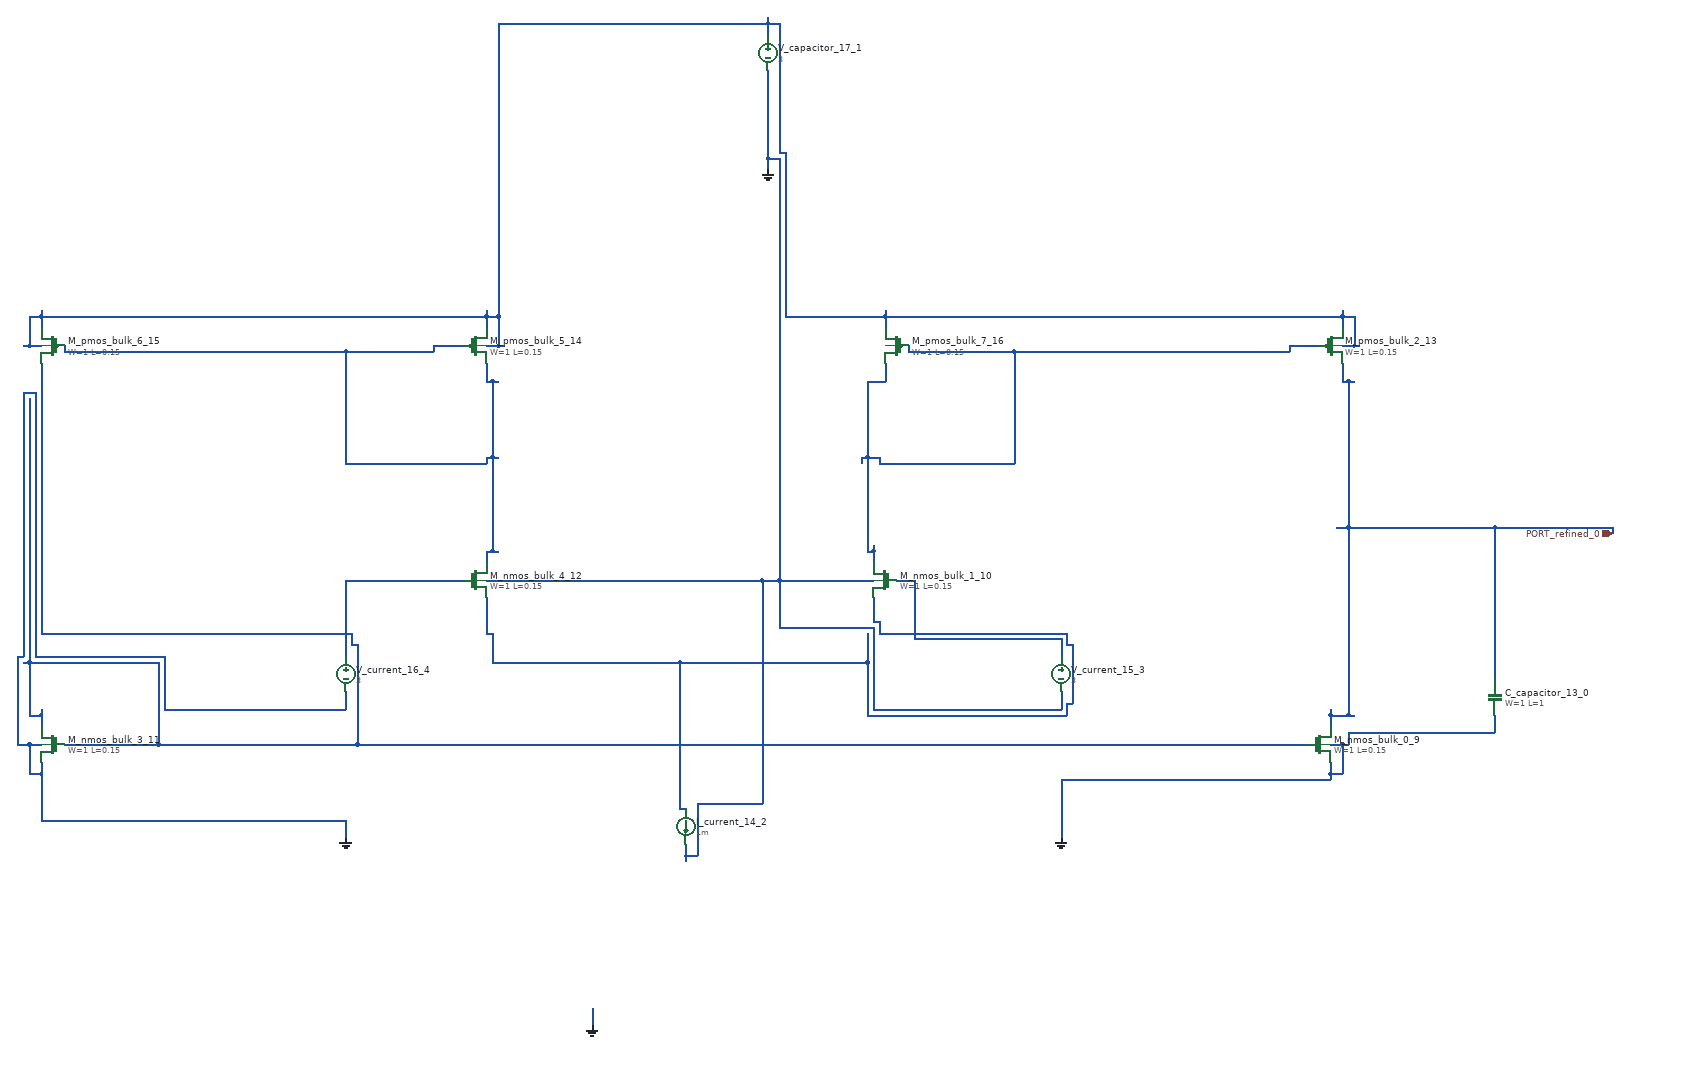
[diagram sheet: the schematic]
v {xschem version=3.4.8 file_version=1.2}
G {}
K {}
V {}
S {}
E {}
C {sky130_fd_pr/cap_mim_m3_1.sym} 3100 1320 2 0 {name="C_capacitor_13_0" model=cap_mim_m3_1 W=1 L=1 MF=1 spiceprefix=X}
C {devices/vsource.sym} 1860 220 0 0 {name="V_capacitor_17_1" value=3 savecurrent=false}
C {devices/isource.sym} 1720 1540 0 0 {name="I_current_14_2" value=1m}
C {devices/vsource.sym} 2360 1280 0 0 {name="V_current_15_3" value=3 savecurrent=false}
C {devices/vsource.sym} 1140 1280 0 0 {name="V_current_16_4" value=3 savecurrent=false}
C {devices/gnd.sym} 1140 1560 0 0 {name="l_gnd_10_5" lab="GND"}
C {devices/gnd.sym} 1560 1880 0 0 {name="l_gnd_11_6" lab="GND"}
C {devices/gnd.sym} 1860 420 0 0 {name="l_gnd_12_7" lab="GND"}
C {devices/gnd.sym} 2360 1560 0 0 {name="l_gnd_9_8" lab="GND"}
C {sky130_fd_pr/nfet_01v8.sym} 2800 1400 0 0 {name="M_nmos_bulk_0_9"
W=1
L=0.15
nf=1 
mult=1
ad="expr('int((@nf + 1)/2) * @W / @nf * 0.29')"
pd="expr('2*int((@nf + 1)/2) * (@W / @nf + 0.29)')"
as="expr('int((@nf + 2)/2) * @W / @nf * 0.29')"
ps="expr('2*int((@nf + 2)/2) * (@W / @nf + 0.29)')"
nrd="expr('0.29 / @W ')" nrs="expr('0.29 / @W ')"
sa=0 sb=0 sd=0
model=nfet_01v8
spiceprefix=X
}
C {sky130_fd_pr/nfet_01v8.sym} 2060 1120 0 1 {name="M_nmos_bulk_1_10"
W=1
L=0.15
nf=1 
mult=1
ad="expr('int((@nf + 1)/2) * @W / @nf * 0.29')"
pd="expr('2*int((@nf + 1)/2) * (@W / @nf + 0.29)')"
as="expr('int((@nf + 2)/2) * @W / @nf * 0.29')"
ps="expr('2*int((@nf + 2)/2) * (@W / @nf + 0.29)')"
nrd="expr('0.29 / @W ')" nrs="expr('0.29 / @W ')"
sa=0 sb=0 sd=0
model=nfet_01v8
spiceprefix=X
}
C {sky130_fd_pr/nfet_01v8.sym} 640 1400 0 1 {name="M_nmos_bulk_3_11"
W=1
L=0.15
nf=1 
mult=1
ad="expr('int((@nf + 1)/2) * @W / @nf * 0.29')"
pd="expr('2*int((@nf + 1)/2) * (@W / @nf + 0.29)')"
as="expr('int((@nf + 2)/2) * @W / @nf * 0.29')"
ps="expr('2*int((@nf + 2)/2) * (@W / @nf + 0.29)')"
nrd="expr('0.29 / @W ')" nrs="expr('0.29 / @W ')"
sa=0 sb=0 sd=0
model=nfet_01v8
spiceprefix=X
}
C {sky130_fd_pr/nfet_01v8.sym} 1360 1120 0 0 {name="M_nmos_bulk_4_12"
W=1
L=0.15
nf=1 
mult=1
ad="expr('int((@nf + 1)/2) * @W / @nf * 0.29')"
pd="expr('2*int((@nf + 1)/2) * (@W / @nf + 0.29)')"
as="expr('int((@nf + 2)/2) * @W / @nf * 0.29')"
ps="expr('2*int((@nf + 2)/2) * (@W / @nf + 0.29)')"
nrd="expr('0.29 / @W ')" nrs="expr('0.29 / @W ')"
sa=0 sb=0 sd=0
model=nfet_01v8
spiceprefix=X
}
C {sky130_fd_pr/pfet_01v8.sym} 2820 720 0 0 {name="M_pmos_bulk_2_13"
W=1
L=0.15
nf=1
mult=1
ad="expr('int((@nf + 1)/2) * @W / @nf * 0.29')"
pd="expr('2*int((@nf + 1)/2) * (@W / @nf + 0.29)')"
as="expr('int((@nf + 2)/2) * @W / @nf * 0.29')"
ps="expr('2*int((@nf + 2)/2) * (@W / @nf + 0.29)')"
nrd="expr('0.29 / @W ')" nrs="expr('0.29 / @W ')"
sa=0 sb=0 sd=0
model=pfet_01v8
spiceprefix=X
}
C {sky130_fd_pr/pfet_01v8.sym} 1360 720 0 0 {name="M_pmos_bulk_5_14"
W=1
L=0.15
nf=1
mult=1
ad="expr('int((@nf + 1)/2) * @W / @nf * 0.29')"
pd="expr('2*int((@nf + 1)/2) * (@W / @nf + 0.29)')"
as="expr('int((@nf + 2)/2) * @W / @nf * 0.29')"
ps="expr('2*int((@nf + 2)/2) * (@W / @nf + 0.29)')"
nrd="expr('0.29 / @W ')" nrs="expr('0.29 / @W ')"
sa=0 sb=0 sd=0
model=pfet_01v8
spiceprefix=X
}
C {sky130_fd_pr/pfet_01v8.sym} 640 720 0 1 {name="M_pmos_bulk_6_15"
W=1
L=0.15
nf=1
mult=1
ad="expr('int((@nf + 1)/2) * @W / @nf * 0.29')"
pd="expr('2*int((@nf + 1)/2) * (@W / @nf + 0.29)')"
as="expr('int((@nf + 2)/2) * @W / @nf * 0.29')"
ps="expr('2*int((@nf + 2)/2) * (@W / @nf + 0.29)')"
nrd="expr('0.29 / @W ')" nrs="expr('0.29 / @W ')"
sa=0 sb=0 sd=0
model=pfet_01v8
spiceprefix=X
}
C {sky130_fd_pr/pfet3_01v8.sym} 2080 720 0 1 {name="M_pmos_bulk_7_16"
W=1
L=0.15
body=VDD
nf=1
mult=1
ad="expr('int((@nf + 1)/2) * @W / @nf * 0.29')"
pd="expr('2*int((@nf + 1)/2) * (@W / @nf + 0.29)')"
as="expr('int((@nf + 2)/2) * @W / @nf * 0.29')"
ps="expr('2*int((@nf + 2)/2) * (@W / @nf + 0.29)')"
nrd="expr('0.29 / @W ')" nrs="expr('0.29 / @W ')"
sa=0 sb=0 sd=0
model=pfet_01v8
spiceprefix=X
}
C {devices/ipin.sym} 3300 1040 0 0 {name="p_port_8_17" lab="PORT_refined_0"}
N 2820 1350 2850 1350 {}
N 2850 1350 2860 1350 {}
N 2830 1030 2850 1030 {}
N 2850 1030 3100 1030 {}
N 3100 1030 3300 1030 {}
N 2840 780 2850 780 {}
N 2850 780 2860 780 {}
N 2820 1370 2820 1350 {}
N 2820 1350 2820 1340 {}
N 2840 780 2840 750 {}
N 2850 1350 2850 1030 {}
N 2850 1030 2850 780 {}
N 3100 1300 3100 1290 {}
N 3100 1290 3100 1030 {}
N 3300 1040 3300 1030 {}
N 1720 1590 1740 1590 {}
N 620 1530 1140 1530 {}
N 1740 1500 1850 1500 {}
N 2360 1460 2820 1460 {}
N 600 1450 620 1450 {}
N 2820 1450 2840 1450 {}
N 580 1400 600 1400 {}
N 600 1400 620 1400 {}
N 2820 1400 2840 1400 {}
N 2840 1400 2850 1400 {}
N 2850 1380 3100 1380 {}
N 830 1340 1140 1340 {}
N 2040 1340 2360 1340 {}
N 580 1250 590 1250 {}
N 610 1250 830 1250 {}
N 1880 1200 2040 1200 {}
N 1380 1120 1850 1120 {}
N 1850 1120 1880 1120 {}
N 1880 1120 2040 1120 {}
N 590 800 610 800 {}
N 1860 400 1880 400 {}
N 580 1400 580 1250 {}
N 590 1250 590 800 {}
N 600 1450 600 1400 {}
N 610 1250 610 800 {}
N 620 1530 620 1450 {}
N 620 1450 620 1430 {}
N 830 1340 830 1250 {}
N 1140 1560 1140 1530 {}
N 1140 1340 1140 1310 {}
N 1560 1880 1560 1850 {}
N 1720 1600 1720 1590 {}
N 1720 1590 1720 1570 {}
N 1740 1590 1740 1500 {}
N 1850 1500 1850 1120 {}
N 1860 420 1860 400 {}
N 1860 400 1860 250 {}
N 1880 1200 1880 1120 {}
N 1880 1120 1880 400 {}
N 2040 1340 2040 1200 {}
N 2360 1560 2360 1460 {}
N 2360 1340 2360 1310 {}
N 2820 1460 2820 1450 {}
N 2820 1450 2820 1430 {}
N 2840 1450 2840 1400 {}
N 2850 1400 2850 1380 {}
N 3100 1380 3100 1350 {}
N 660 1400 820 1400 {}
N 820 1400 1160 1400 {}
N 1160 1400 2780 1400 {}
N 600 1350 620 1350 {}
N 590 1260 600 1260 {}
N 600 1260 820 1260 {}
N 1150 1230 1160 1230 {}
N 620 1210 1150 1210 {}
N 600 1350 600 1260 {}
N 600 1260 600 810 {}
N 620 1370 620 1350 {}
N 620 1350 620 1340 {}
N 620 1210 620 750 {}
N 820 1400 820 1260 {}
N 1150 1230 1150 1210 {}
N 1160 1400 1160 1230 {}
N 1710 1510 1720 1510 {}
N 2030 1350 2370 1350 {}
N 2370 1330 2380 1330 {}
N 1390 1260 1710 1260 {}
N 1710 1260 2030 1260 {}
N 2370 1230 2380 1230 {}
N 1380 1210 1390 1210 {}
N 2050 1210 2370 1210 {}
N 2040 1190 2050 1190 {}
N 1380 1210 1380 1150 {}
N 1390 1260 1390 1210 {}
N 1710 1510 1710 1260 {}
N 2030 1350 2030 1260 {}
N 2030 1260 2030 1210 {}
N 2040 1190 2040 1150 {}
N 2050 1210 2050 1190 {}
N 2370 1350 2370 1330 {}
N 2370 1230 2370 1210 {}
N 2380 1330 2380 1230 {}
N 590 720 600 720 {}
N 600 720 620 720 {}
N 1380 720 1400 720 {}
N 1400 720 1410 720 {}
N 2840 720 2860 720 {}
N 2860 720 2870 720 {}
N 600 670 620 670 {}
N 620 670 1380 670 {}
N 1380 670 1400 670 {}
N 1890 670 2060 670 {}
N 2060 670 2840 670 {}
N 2840 670 2860 670 {}
N 1880 390 1890 390 {}
N 1400 170 1860 170 {}
N 1860 170 1880 170 {}
N 600 720 600 670 {}
N 620 690 620 670 {}
N 620 670 620 660 {}
N 1380 690 1380 670 {}
N 1380 670 1380 660 {}
N 1400 720 1400 670 {}
N 1400 670 1400 170 {}
N 1860 190 1860 170 {}
N 1860 170 1860 160 {}
N 1880 390 1880 170 {}
N 1890 670 1890 390 {}
N 2060 690 2060 670 {}
N 2060 670 2060 660 {}
N 2840 690 2840 670 {}
N 2840 670 2840 660 {}
N 2860 720 2860 670 {}
N 2030 1070 2040 1070 {}
N 2050 920 2280 920 {}
N 2020 910 2030 910 {}
N 2030 910 2050 910 {}
N 2030 780 2060 780 {}
N 2100 730 2280 730 {}
N 2280 730 2750 730 {}
N 2750 720 2800 720 {}
N 2020 920 2020 910 {}
N 2030 1070 2030 910 {}
N 2030 910 2030 780 {}
N 2040 1090 2040 1070 {}
N 2040 1070 2040 1060 {}
N 2050 920 2050 910 {}
N 2060 780 2060 750 {}
N 2100 730 2100 720 {}
N 2280 920 2280 730 {}
N 2750 730 2750 720 {}
N 2110 1220 2360 1220 {}
N 2080 1120 2110 1120 {}
N 2110 1220 2110 1120 {}
N 2360 1250 2360 1220 {}
N 1380 1070 1390 1070 {}
N 1390 1070 1400 1070 {}
N 1140 920 1380 920 {}
N 1380 910 1390 910 {}
N 1390 910 1400 910 {}
N 1380 780 1390 780 {}
N 1390 780 1400 780 {}
N 660 730 1140 730 {}
N 1140 730 1290 730 {}
N 1290 720 1340 720 {}
N 660 730 660 720 {}
N 1140 920 1140 730 {}
N 1290 730 1290 720 {}
N 1380 1090 1380 1070 {}
N 1380 920 1380 910 {}
N 1380 780 1380 750 {}
N 1390 1070 1390 910 {}
N 1390 910 1390 780 {}
N 1140 1120 1340 1120 {}
N 1140 1250 1140 1120 {}
